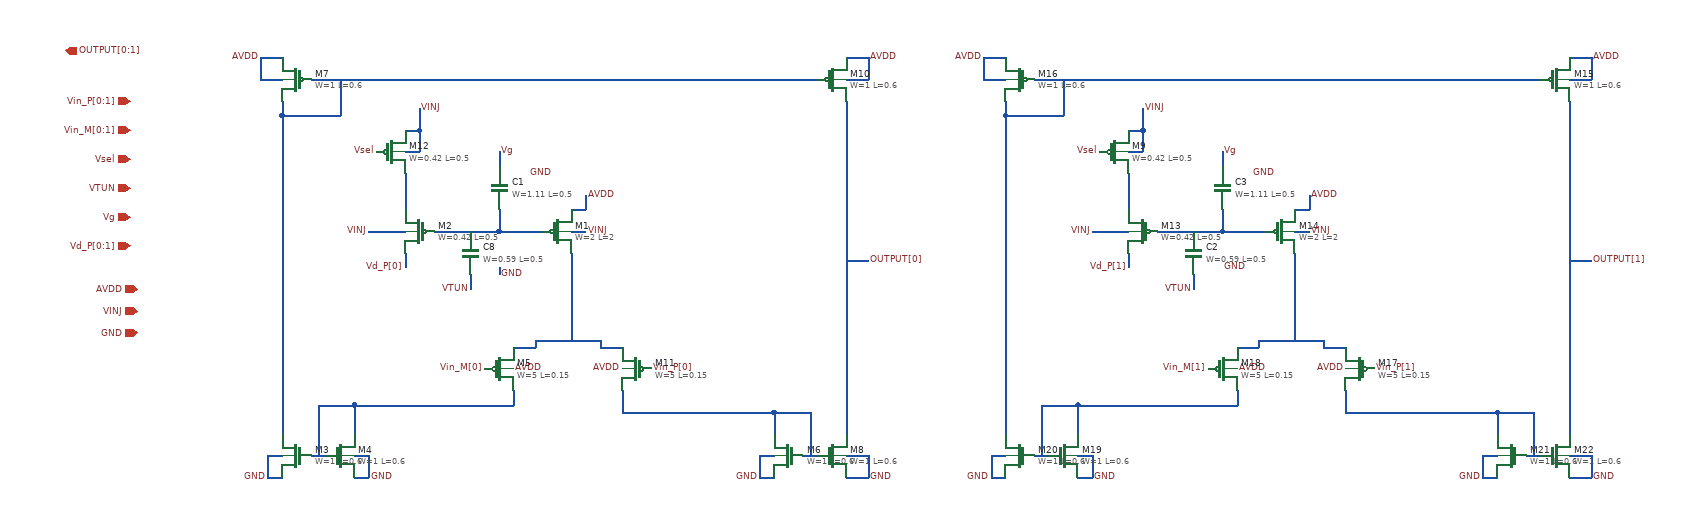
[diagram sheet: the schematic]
v {xschem version=3.4.8RC file_version=1.3}
G {}
K {}
V {}
S {}
F {}
E {}
N 640 -460 670 -460 {
lab=#net1}
N 670 -470 670 -460 {
lab=#net1}
N 670 -470 690 -470 {
lab=#net1}
N 760 -460 790 -460 {
lab=#net1}
N 760 -470 760 -460 {
lab=#net1}
N 740 -470 760 -470 {
lab=#net1}
N 690 -470 710 -470 {
lab=#net1}
N 710 -470 740 -470 {
lab=#net1}
N 360 -310 380 -310 {
lab=#net2}
N 370 -350 370 -310 {
lab=#net2}
N 360 -830 420 -830 {
lab=#net3}
N 1000 -370 1000 -340 {
lab=#net4}
N 1040 -310 1060 -310 {
lab=#net4}
N 1050 -350 1050 -310 {
lab=#net4}
N 420 -830 510 -830 {
lab=#net3}
N 720 -590 720 -500 {
lab=#net1}
N 490 -700 490 -680 {
lab=#net5}
N 440 -620 490 -620 {
lab=VINJ}
N 740 -830 1060 -830 {
lab=#net3}
N 400 -830 400 -780 {
lab=#net3}
N 320 -780 400 -780 {
lab=#net3}
N 320 -800 320 -780 {
lab=#net3}
N 1100 -800 1100 -340 {
lab=OUTPUT[0]}
N 320 -780 320 -340 {
lab=#net3}
N 640 -400 640 -390 {
lab=#net2}
N 420 -380 640 -380 {
lab=#net2}
N 640 -390 640 -380 {
lab=#net2}
N 790 -400 790 -380 {
lab=#net4}
N 790 -370 1000 -370 {
lab=#net4}
N 790 -380 790 -370 {
lab=#net4}
N 370 -380 420 -380 {
lab=#net2}
N 370 -380 370 -350 {
lab=#net2}
N 420 -380 420 -340 {
lab=#net2}
N 1000 -370 1050 -370 {
lab=#net4}
N 1050 -370 1050 -350 {
lab=#net4}
N 510 -830 740 -830 {
lab=#net3}
N 720 -500 720 -470 {
lab=#net1}
N 1100 -580 1130 -580 {
lab=OUTPUT[0]}
N 490 -760 510 -760 {
lab=VINJ}
N 510 -760 510 -730 {
lab=VINJ}
N 490 -730 510 -730 {
lab=VINJ}
N 510 -790 510 -760 {
lab=VINJ}
N 620 -570 620 -560 {
lab=GND}
N 490 -680 490 -650 {
lab=#net5}
N 620 -650 620 -620 {
lab=#net6}
N 290 -860 320 -860 {
lab=AVDD}
N 290 -860 290 -830 {
lab=AVDD}
N 290 -830 320 -830 {
lab=AVDD}
N 1100 -860 1130 -860 {
lab=AVDD}
N 1130 -860 1130 -830 {
lab=AVDD}
N 1100 -830 1130 -830 {
lab=AVDD}
N 490 -590 490 -570 {
lab=Vd_P[0]}
N 720 -620 740 -620 {
lab=VINJ}
N 720 -650 740 -650 {
lab=AVDD}
N 740 -670 740 -650 {
lab=AVDD}
N 300 -310 320 -310 {
lab=GND}
N 300 -310 300 -280 {
lab=GND}
N 300 -280 320 -280 {
lab=GND}
N 420 -310 440 -310 {
lab=GND}
N 440 -310 440 -280 {
lab=GND}
N 420 -280 440 -280 {
lab=GND}
N 980 -310 1000 -310 {
lab=GND}
N 980 -310 980 -280 {
lab=GND}
N 980 -280 1000 -280 {
lab=GND}
N 1100 -310 1130 -310 {
lab=GND}
N 1130 -310 1130 -280 {
lab=GND}
N 1100 -280 1130 -280 {
lab=GND}
N 580 -620 620 -620 {
lab=#net6}
N 530 -620 580 -620 {
lab=#net6}
N 620 -620 680 -620 {
lab=#net6}
N 1640 -460 1670 -460 {
lab=#net7}
N 1670 -470 1670 -460 {
lab=#net7}
N 1670 -470 1690 -470 {
lab=#net7}
N 1760 -460 1790 -460 {
lab=#net7}
N 1760 -470 1760 -460 {
lab=#net7}
N 1740 -470 1760 -470 {
lab=#net7}
N 1690 -470 1710 -470 {
lab=#net7}
N 1710 -470 1740 -470 {
lab=#net7}
N 1360 -310 1380 -310 {
lab=#net8}
N 1370 -350 1370 -310 {
lab=#net8}
N 1360 -830 1420 -830 {
lab=#net9}
N 2000 -370 2000 -340 {
lab=#net10}
N 2040 -310 2060 -310 {
lab=#net10}
N 2050 -350 2050 -310 {
lab=#net10}
N 1420 -830 1510 -830 {
lab=#net9}
N 1720 -590 1720 -500 {
lab=#net7}
N 1490 -700 1490 -680 {
lab=#net11}
N 1440 -620 1490 -620 {
lab=VINJ}
N 1740 -830 2060 -830 {
lab=#net9}
N 1400 -830 1400 -780 {
lab=#net9}
N 1320 -780 1400 -780 {
lab=#net9}
N 1320 -800 1320 -780 {
lab=#net9}
N 2100 -800 2100 -340 {
lab=OUTPUT[1]}
N 1320 -780 1320 -340 {
lab=#net9}
N 1640 -400 1640 -390 {
lab=#net8}
N 1420 -380 1640 -380 {
lab=#net8}
N 1640 -390 1640 -380 {
lab=#net8}
N 1790 -400 1790 -380 {
lab=#net10}
N 1790 -370 2000 -370 {
lab=#net10}
N 1790 -380 1790 -370 {
lab=#net10}
N 1370 -380 1420 -380 {
lab=#net8}
N 1370 -380 1370 -350 {
lab=#net8}
N 1420 -380 1420 -340 {
lab=#net8}
N 2000 -370 2050 -370 {
lab=#net10}
N 2050 -370 2050 -350 {
lab=#net10}
N 1510 -830 1740 -830 {
lab=#net9}
N 1720 -500 1720 -470 {
lab=#net7}
N 2100 -580 2130 -580 {
lab=OUTPUT[1]}
N 1490 -760 1510 -760 {
lab=VINJ}
N 1510 -760 1510 -730 {
lab=VINJ}
N 1490 -730 1510 -730 {
lab=VINJ}
N 1510 -790 1510 -760 {
lab=VINJ}
N 1490 -680 1490 -650 {
lab=#net11}
N 1620 -650 1620 -620 {
lab=#net12}
N 1290 -860 1320 -860 {
lab=AVDD}
N 1290 -860 1290 -830 {
lab=AVDD}
N 1290 -830 1320 -830 {
lab=AVDD}
N 2100 -860 2130 -860 {
lab=AVDD}
N 2130 -860 2130 -830 {
lab=AVDD}
N 2100 -830 2130 -830 {
lab=AVDD}
N 1490 -590 1490 -570 {
lab=Vd_P[1]}
N 1720 -620 1740 -620 {
lab=VINJ}
N 1720 -650 1740 -650 {
lab=VDD}
N 1740 -670 1740 -650 {
lab=VDD}
N 1300 -310 1320 -310 {
lab=GND}
N 1300 -310 1300 -280 {
lab=GND}
N 1300 -280 1320 -280 {
lab=GND}
N 1420 -310 1440 -310 {
lab=GND}
N 1440 -310 1440 -280 {
lab=GND}
N 1420 -280 1440 -280 {
lab=GND}
N 1980 -310 2000 -310 {
lab=GND}
N 1980 -310 1980 -280 {
lab=GND}
N 1980 -280 2000 -280 {
lab=GND}
N 2100 -310 2130 -310 {
lab=GND}
N 2130 -310 2130 -280 {
lab=GND}
N 2100 -280 2130 -280 {
lab=GND}
N 1580 -620 1620 -620 {
lab=#net12}
N 1530 -620 1580 -620 {
lab=#net12}
N 1620 -620 1680 -620 {
lab=#net12}
N 1580 -560 1580 -540 {
lab=VTUN}
N 1620 -730 1620 -710 {
lab=Vg}
N 580 -560 580 -540 {
lab=VTUN}
N 620 -730 620 -710 {
lab=Vg}
C {lab_pin.sym} 830 -430 2 0 {name=p1 sig_type=std_logic lab=Vin_P[0]}
C {lab_pin.sym} 600 -430 0 0 {name=p2 sig_type=std_logic lab=Vin_M[0]}
C {lab_pin.sym} 620 -730 2 0 {name=p9 sig_type=std_logic lab=Vg



}
C {lab_pin.sym} 580 -540 0 0 {name=p10 sig_type=std_logic lab=VTUN



}
C {lab_pin.sym} 740 -670 2 0 {name=p11 sig_type=std_logic lab=AVDD


}
C {lab_pin.sym} 440 -620 0 0 {name=p12 sig_type=std_logic lab=VINJ


}
C {lab_pin.sym} 510 -790 2 0 {name=p13 sig_type=std_logic lab=VINJ


}
C {lab_pin.sym} 640 -430 2 0 {name=p18 sig_type=std_logic lab=AVDD


}
C {lab_pin.sym} 790 -430 0 0 {name=p20 sig_type=std_logic lab=AVDD



}
C {ipin.sym} 110 -800 0 0 {name=p21 lab=Vin_P[0:1]}
C {ipin.sym} 110 -760 0 0 {name=p22 lab=Vin_M[0:1]}
C {ipin.sym} 110 -720 0 0 {name=p23 lab=Vsel
}
C {ipin.sym} 110 -680 0 0 {name=p24 lab=VTUN
}
C {ipin.sym} 110 -640 0 0 {name=p25 lab=Vg}
C {ipin.sym} 120 -510 0 0 {name=p27 lab=VINJ
}
C {lab_pin.sym} 1130 -580 2 0 {name=p28 sig_type=std_logic lab=OUTPUT[0]


}
C {opin.sym} 20 -870 0 0 {name=p29 lab=OUTPUT[0:1]}
C {ipin.sym} 120 -540 0 0 {name=p3 lab=AVDD}
C {ipin.sym} 120 -480 0 0 {name=p32 lab=GND}
C {lab_pin.sym} 440 -280 2 0 {name=p33 sig_type=std_logic lab=GND

}
C {lab_pin.sym} 300 -280 0 0 {name=p34 sig_type=std_logic lab=GND



}
C {lab_pin.sym} 1130 -280 2 0 {name=p35 sig_type=std_logic lab=GND


}
C {lab_pin.sym} 980 -280 0 0 {name=p36 sig_type=std_logic lab=GND


}
C {lab_pin.sym} 290 -860 0 0 {name=p37 sig_type=std_logic lab=AVDD


}
C {lab_pin.sym} 1130 -860 2 0 {name=p38 sig_type=std_logic lab=AVDD


}
C {sky130_fd_pr/cap_var_hvt.sym} 580 -590 0 1 {name=C8 model=cap_var W=0.59 L=0.5 VM=1 spiceprefix=X}
C {sky130_fd_pr/pfet_g5v0d10v5.sym} 470 -730 0 0 {name=M12
L=0.5
W=0.42
nf=1
mult=1
ad="'int((nf+1)/2) * W/nf * 0.29'" 
pd="'2*int((nf+1)/2) * (W/nf + 0.29)'"
as="'int((nf+2)/2) * W/nf * 0.29'" 
ps="'2*int((nf+2)/2) * (W/nf + 0.29)'"
nrd="'0.29 / W'" nrs="'0.29 / W'"
sa=0 sb=0 sd=0
model=pfet_g5v0d10v5
spiceprefix=X
}
C {sky130_fd_pr/pfet_g5v0d10v5.sym} 510 -620 0 1 {name=M2
L=0.5
W=0.42
nf=1
mult=1
ad="'int((nf+1)/2) * W/nf * 0.29'" 
pd="'2*int((nf+1)/2) * (W/nf + 0.29)'"
as="'int((nf+2)/2) * W/nf * 0.29'" 
ps="'2*int((nf+2)/2) * (W/nf + 0.29)'"
nrd="'0.29 / W'" nrs="'0.29 / W'"
sa=0 sb=0 sd=0
model=pfet_g5v0d10v5
spiceprefix=X
}
C {lab_pin.sym} 450 -730 0 0 {name=p4 sig_type=std_logic lab=Vsel
}
C {lab_pin.sym} 490 -570 0 0 {name=p14 sig_type=std_logic lab=Vd_P[0]


}
C {sky130_fd_pr/cap_var_hvt.sym} 620 -680 2 0 {name=C1 model=cap_var W=1.11 L=0.5 VM=1 spiceprefix=X}
C {sky130_fd_pr/pfet_g5v0d10v5.sym} 700 -620 0 0 {name=M1
L=2
W=2
nf=1
mult=1
ad="'int((nf+1)/2) * W/nf * 0.29'" 
pd="'2*int((nf+1)/2) * (W/nf + 0.29)'"
as="'int((nf+2)/2) * W/nf * 0.29'" 
ps="'2*int((nf+2)/2) * (W/nf + 0.29)'"
nrd="'0.29 / W'" nrs="'0.29 / W'"
sa=0 sb=0 sd=0
model=pfet_g5v0d10v5
spiceprefix=X
}
C {sky130_fd_pr/pfet_01v8.sym} 1080 -830 0 0 {name=M10
W=1
L=0.6
nf=1
mult=1
ad="'int((nf+1)/2) * W/nf * 0.29'" 
pd="'2*int((nf+1)/2) * (W/nf + 0.29)'"
as="'int((nf+2)/2) * W/nf * 0.29'" 
ps="'2*int((nf+2)/2) * (W/nf + 0.29)'"
nrd="'0.29 / W'" nrs="'0.29 / W'"
sa=0 sb=0 sd=0
model=pfet_01v8
spiceprefix=X
}
C {sky130_fd_pr/pfet_01v8.sym} 340 -830 2 0 {name=M7
W=1
L=0.6
nf=1
mult=1
ad="'int((nf+1)/2) * W/nf * 0.29'" 
pd="'2*int((nf+1)/2) * (W/nf + 0.29)'"
as="'int((nf+2)/2) * W/nf * 0.29'" 
ps="'2*int((nf+2)/2) * (W/nf + 0.29)'"
nrd="'0.29 / W'" nrs="'0.29 / W'"
sa=0 sb=0 sd=0
model=pfet_01v8
spiceprefix=X
}
C {sky130_fd_pr/pfet_01v8.sym} 810 -430 2 0 {name=M11
W=5
L=0.15
nf=1
mult=1
ad="'int((nf+1)/2) * W/nf * 0.29'" 
pd="'2*int((nf+1)/2) * (W/nf + 0.29)'"
as="'int((nf+2)/2) * W/nf * 0.29'" 
ps="'2*int((nf+2)/2) * (W/nf + 0.29)'"
nrd="'0.29 / W'" nrs="'0.29 / W'"
sa=0 sb=0 sd=0
model=pfet_01v8
spiceprefix=X
}
C {sky130_fd_pr/pfet_01v8.sym} 620 -430 0 0 {name=M5
W=5
L=0.15
nf=1
mult=1
ad="'int((nf+1)/2) * W/nf * 0.29'" 
pd="'2*int((nf+1)/2) * (W/nf + 0.29)'"
as="'int((nf+2)/2) * W/nf * 0.29'" 
ps="'2*int((nf+2)/2) * (W/nf + 0.29)'"
nrd="'0.29 / W'" nrs="'0.29 / W'"
sa=0 sb=0 sd=0
model=pfet_01v8
spiceprefix=X
}
C {sky130_fd_pr/nfet_01v8.sym} 400 -310 0 0 {name=M4
W=1
L=0.6
nf=1 
mult=1
ad="'int((nf+1)/2) * W/nf * 0.29'" 
pd="'2*int((nf+1)/2) * (W/nf + 0.29)'"
as="'int((nf+2)/2) * W/nf * 0.29'" 
ps="'2*int((nf+2)/2) * (W/nf + 0.29)'"
nrd="'0.29 / W'" nrs="'0.29 / W'"
sa=0 sb=0 sd=0
model=nfet_01v8
spiceprefix=X
}
C {sky130_fd_pr/nfet_01v8.sym} 340 -310 2 0 {name=M3
W=1
L=0.6
nf=1 
mult=1
ad="'int((nf+1)/2) * W/nf * 0.29'" 
pd="'2*int((nf+1)/2) * (W/nf + 0.29)'"
as="'int((nf+2)/2) * W/nf * 0.29'" 
ps="'2*int((nf+2)/2) * (W/nf + 0.29)'"
nrd="'0.29 / W'" nrs="'0.29 / W'"
sa=0 sb=0 sd=0
model=nfet_01v8
spiceprefix=X
}
C {sky130_fd_pr/nfet_01v8.sym} 1020 -310 2 0 {name=M6
W=1
L=0.6
nf=1 
mult=1
ad="'int((nf+1)/2) * W/nf * 0.29'" 
pd="'2*int((nf+1)/2) * (W/nf + 0.29)'"
as="'int((nf+2)/2) * W/nf * 0.29'" 
ps="'2*int((nf+2)/2) * (W/nf + 0.29)'"
nrd="'0.29 / W'" nrs="'0.29 / W'"
sa=0 sb=0 sd=0
model=nfet_01v8
spiceprefix=X
}
C {sky130_fd_pr/nfet_01v8.sym} 1080 -310 0 0 {name=M8
W=1
L=0.6
nf=1 
mult=1
ad="'int((nf+1)/2) * W/nf * 0.29'" 
pd="'2*int((nf+1)/2) * (W/nf + 0.29)'"
as="'int((nf+2)/2) * W/nf * 0.29'" 
ps="'2*int((nf+2)/2) * (W/nf + 0.29)'"
nrd="'0.29 / W'" nrs="'0.29 / W'"
sa=0 sb=0 sd=0
model=nfet_01v8
spiceprefix=X
}
C {lab_pin.sym} 1830 -430 2 0 {name=p5 sig_type=std_logic lab=Vin_P[1]}
C {lab_pin.sym} 1600 -430 0 0 {name=p6 sig_type=std_logic lab=Vin_M[1]}
C {lab_pin.sym} 1620 -730 2 0 {name=p7 sig_type=std_logic lab=Vg



}
C {lab_pin.sym} 1580 -540 0 0 {name=p8 sig_type=std_logic lab=VTUN



}
C {lab_pin.sym} 1740 -670 2 0 {name=p15 sig_type=std_logic lab=AVDD


}
C {lab_pin.sym} 1440 -620 0 0 {name=p16 sig_type=std_logic lab=VINJ


}
C {lab_pin.sym} 1510 -790 2 0 {name=p17 sig_type=std_logic lab=VINJ


}
C {lab_pin.sym} 1640 -430 2 0 {name=p19 sig_type=std_logic lab=AVDD


}
C {lab_pin.sym} 1790 -430 0 0 {name=p30 sig_type=std_logic lab=AVDD



}
C {lab_pin.sym} 2130 -580 2 0 {name=p39 sig_type=std_logic lab=OUTPUT[1]


}
C {lab_pin.sym} 1440 -280 2 0 {name=p40 sig_type=std_logic lab=GND

}
C {lab_pin.sym} 1300 -280 0 0 {name=p41 sig_type=std_logic lab=GND


}
C {lab_pin.sym} 2130 -280 2 0 {name=p42 sig_type=std_logic lab=GND


}
C {lab_pin.sym} 1980 -280 0 0 {name=p43 sig_type=std_logic lab=GND


}
C {lab_pin.sym} 1290 -860 0 0 {name=p44 sig_type=std_logic lab=AVDD


}
C {lab_pin.sym} 2130 -860 2 0 {name=p45 sig_type=std_logic lab=AVDD


}
C {sky130_fd_pr/cap_var_hvt.sym} 1580 -590 0 1 {name=C2 model=cap_var W=0.59 L=0.5 VM=1 spiceprefix=X}
C {sky130_fd_pr/pfet_g5v0d10v5.sym} 1470 -730 0 0 {name=M9
L=0.5
W=0.42
nf=1
mult=1
ad="'int((nf+1)/2) * W/nf * 0.29'" 
pd="'2*int((nf+1)/2) * (W/nf + 0.29)'"
as="'int((nf+2)/2) * W/nf * 0.29'" 
ps="'2*int((nf+2)/2) * (W/nf + 0.29)'"
nrd="'0.29 / W'" nrs="'0.29 / W'"
sa=0 sb=0 sd=0
model=pfet_g5v0d10v5
spiceprefix=X
}
C {sky130_fd_pr/pfet_g5v0d10v5.sym} 1510 -620 0 1 {name=M13
L=0.5
W=0.42
nf=1
mult=1
ad="'int((nf+1)/2) * W/nf * 0.29'" 
pd="'2*int((nf+1)/2) * (W/nf + 0.29)'"
as="'int((nf+2)/2) * W/nf * 0.29'" 
ps="'2*int((nf+2)/2) * (W/nf + 0.29)'"
nrd="'0.29 / W'" nrs="'0.29 / W'"
sa=0 sb=0 sd=0
model=pfet_g5v0d10v5
spiceprefix=X
}
C {lab_pin.sym} 1450 -730 0 0 {name=p46 sig_type=std_logic lab=Vsel
}
C {lab_pin.sym} 1490 -570 0 0 {name=p47 sig_type=std_logic lab=Vd_P[1]


}
C {sky130_fd_pr/cap_var_hvt.sym} 1620 -680 2 0 {name=C3 model=cap_var W=1.11 L=0.5 VM=1 spiceprefix=X}
C {sky130_fd_pr/pfet_g5v0d10v5.sym} 1700 -620 0 0 {name=M14
L=2
W=2
nf=1
mult=1
ad="'int((nf+1)/2) * W/nf * 0.29'" 
pd="'2*int((nf+1)/2) * (W/nf + 0.29)'"
as="'int((nf+2)/2) * W/nf * 0.29'" 
ps="'2*int((nf+2)/2) * (W/nf + 0.29)'"
nrd="'0.29 / W'" nrs="'0.29 / W'"
sa=0 sb=0 sd=0
model=pfet_g5v0d10v5
spiceprefix=X
}
C {sky130_fd_pr/pfet_01v8.sym} 2080 -830 0 0 {name=M15
W=1
L=0.6
nf=1
mult=1
ad="'int((nf+1)/2) * W/nf * 0.29'" 
pd="'2*int((nf+1)/2) * (W/nf + 0.29)'"
as="'int((nf+2)/2) * W/nf * 0.29'" 
ps="'2*int((nf+2)/2) * (W/nf + 0.29)'"
nrd="'0.29 / W'" nrs="'0.29 / W'"
sa=0 sb=0 sd=0
model=pfet_01v8
spiceprefix=X
}
C {sky130_fd_pr/pfet_01v8.sym} 1340 -830 2 0 {name=M16
W=1
L=0.6
nf=1
mult=1
ad="'int((nf+1)/2) * W/nf * 0.29'" 
pd="'2*int((nf+1)/2) * (W/nf + 0.29)'"
as="'int((nf+2)/2) * W/nf * 0.29'" 
ps="'2*int((nf+2)/2) * (W/nf + 0.29)'"
nrd="'0.29 / W'" nrs="'0.29 / W'"
sa=0 sb=0 sd=0
model=pfet_01v8
spiceprefix=X
}
C {sky130_fd_pr/pfet_01v8.sym} 1810 -430 2 0 {name=M17
W=5
L=0.15
nf=1
mult=1
ad="'int((nf+1)/2) * W/nf * 0.29'" 
pd="'2*int((nf+1)/2) * (W/nf + 0.29)'"
as="'int((nf+2)/2) * W/nf * 0.29'" 
ps="'2*int((nf+2)/2) * (W/nf + 0.29)'"
nrd="'0.29 / W'" nrs="'0.29 / W'"
sa=0 sb=0 sd=0
model=pfet_01v8
spiceprefix=X
}
C {sky130_fd_pr/pfet_01v8.sym} 1620 -430 0 0 {name=M18
W=5
L=0.15
nf=1
mult=1
ad="'int((nf+1)/2) * W/nf * 0.29'" 
pd="'2*int((nf+1)/2) * (W/nf + 0.29)'"
as="'int((nf+2)/2) * W/nf * 0.29'" 
ps="'2*int((nf+2)/2) * (W/nf + 0.29)'"
nrd="'0.29 / W'" nrs="'0.29 / W'"
sa=0 sb=0 sd=0
model=pfet_01v8
spiceprefix=X
}
C {sky130_fd_pr/nfet_01v8.sym} 1400 -310 0 0 {name=M19
W=1
L=0.6
nf=1 
mult=1
ad="'int((nf+1)/2) * W/nf * 0.29'" 
pd="'2*int((nf+1)/2) * (W/nf + 0.29)'"
as="'int((nf+2)/2) * W/nf * 0.29'" 
ps="'2*int((nf+2)/2) * (W/nf + 0.29)'"
nrd="'0.29 / W'" nrs="'0.29 / W'"
sa=0 sb=0 sd=0
model=nfet_01v8
spiceprefix=X
}
C {sky130_fd_pr/nfet_01v8.sym} 1340 -310 2 0 {name=M20
W=1
L=0.6
nf=1 
mult=1
ad="'int((nf+1)/2) * W/nf * 0.29'" 
pd="'2*int((nf+1)/2) * (W/nf + 0.29)'"
as="'int((nf+2)/2) * W/nf * 0.29'" 
ps="'2*int((nf+2)/2) * (W/nf + 0.29)'"
nrd="'0.29 / W'" nrs="'0.29 / W'"
sa=0 sb=0 sd=0
model=nfet_01v8
spiceprefix=X
}
C {sky130_fd_pr/nfet_01v8.sym} 2020 -310 2 0 {name=M21
W=1
L=0.6
nf=1 
mult=1
ad="'int((nf+1)/2) * W/nf * 0.29'" 
pd="'2*int((nf+1)/2) * (W/nf + 0.29)'"
as="'int((nf+2)/2) * W/nf * 0.29'" 
ps="'2*int((nf+2)/2) * (W/nf + 0.29)'"
nrd="'0.29 / W'" nrs="'0.29 / W'"
sa=0 sb=0 sd=0
model=nfet_01v8
spiceprefix=X
}
C {sky130_fd_pr/nfet_01v8.sym} 2080 -310 0 0 {name=M22
W=1
L=0.6
nf=1 
mult=1
ad="'int((nf+1)/2) * W/nf * 0.29'" 
pd="'2*int((nf+1)/2) * (W/nf + 0.29)'"
as="'int((nf+2)/2) * W/nf * 0.29'" 
ps="'2*int((nf+2)/2) * (W/nf + 0.29)'"
nrd="'0.29 / W'" nrs="'0.29 / W'"
sa=0 sb=0 sd=0
model=nfet_01v8
spiceprefix=X
}
C {ipin.sym} 110 -600 0 0 {name=p48 lab=Vd_P[0:1]
}
C {lab_pin.sym} 740 -620 2 0 {name=p31 sig_type=std_logic lab=VINJ


}
C {lab_pin.sym} 1740 -620 2 0 {name=p52 sig_type=std_logic lab=VINJ


}
C {lab_pin.sym} 1620 -570 2 0 {name=p53 sig_type=std_logic lab=GND

}
C {lab_pin.sym} 1660 -700 2 0 {name=p54 sig_type=std_logic lab=GND

}
C {lab_pin.sym} 620 -560 2 0 {name=p55 sig_type=std_logic lab=GND

}
C {lab_pin.sym} 660 -700 2 0 {name=p56 sig_type=std_logic lab=GND


}
